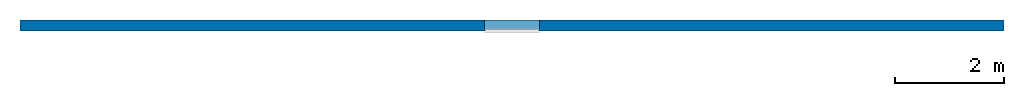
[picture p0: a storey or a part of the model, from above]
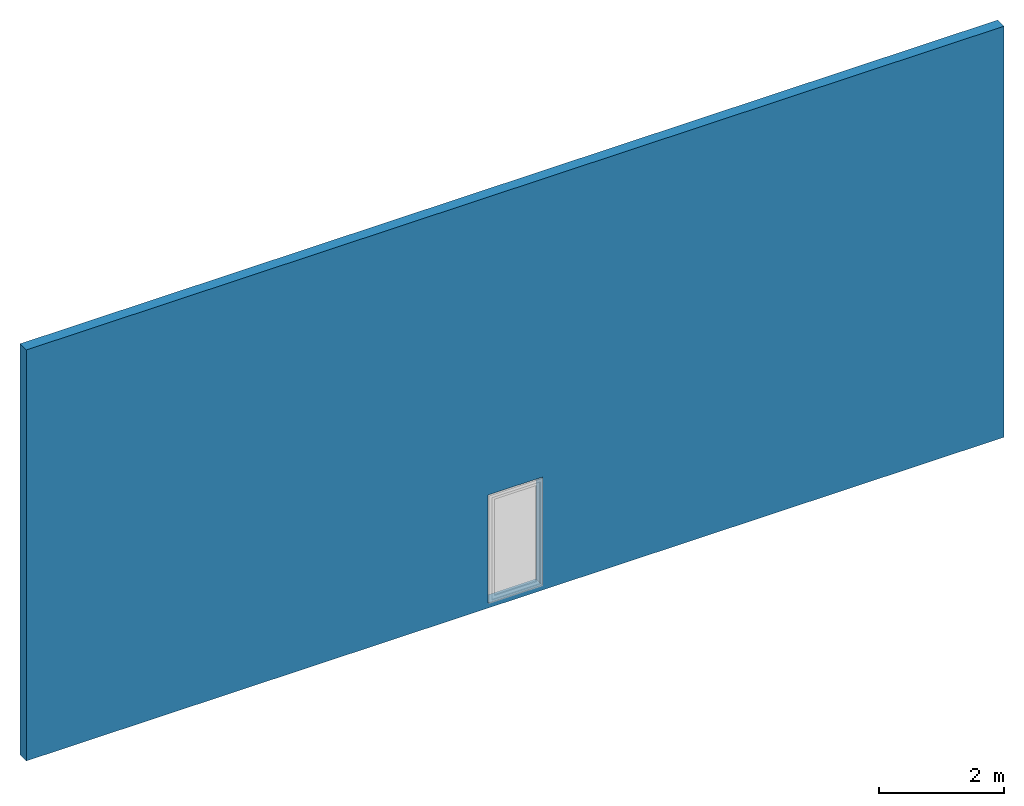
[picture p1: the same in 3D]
Properties of the parts of a building model (IFC2X3)

# File
Description: ViewDefinition [CoordinationView_V2.0]
File name: 0001
Time: 2021-01-22T09:44:21
Written by: The EXPRESS Data Manager Version 5.02.0100.07 : 28 Aug 2013
Made in: 20180328_1600(x64) - Exporter 19.0.1.1 - IU alternativa 19.0.1.1
Comment: STEP Physical File produced by: The EXPRESS Data Manager Version 5.02.0100.07 : 28 Aug 2013 * Module: EDMstepFileFactory/EDMstandAlone * Creation date: Fri Jan 22 09:44:21 2021 * Host: DESKTOP-H3U9LF2 * Database: C:\Users\BIMTOOL3\AppData\Local\Temp\{1FAAF69B-8FC0-4C08-A9C9-90A2DEA5AE0A}\ifc * Database version: 5507 * Database creation date: Fri Jan 22 09:44:20 2021 * Schema: IFC2X3 * Model: DataRepository.ifc * Model creation date: Fri Jan 22 09:44:21 2021 * Header model: DataRepository.ifc_HeaderModel * Header model creation date: Fri Jan 22 09:44:21 2021 * EDMuser: sdai-user * EDMgroup: sdai-group * License ID and type: 5605 : Permanent license. Expiry date: * EDMstepFileFactory options: 020000

# IfcProject, 0001
LongName: Nombre de proyecto; Phase: Estado de proyecto

# IfcSite, Default
RefLatitude: 42, 12, 46, 804504; RefLongitude: -71, -2, 0, -602416; RefElevation: 0 mm

# IfcBuilding
Pset_BuildingCommon - NumberOfStoreys: 1

# IfcBuildingStorey, Nivel 1
LongName: Nivel 1; Elevation: 0 mm

# IfcBuildingElementProxy: 5.1 REH_ED-60 H Z74, 5.1 REH_ED-60 H Z74 :5.1 REH_ED-60 H Z74:347606
In: Nivel 1
Type - Material: Glass, RAU-PVC
Pset_BuildingElementProxyCommon - Reference: 5.1 REH_ED-60 H Z74
Pset_ManufacturerTypeInformation - Manufacturer: REHAU

# IfcWallStandardCase: Muro básico:Genérico - 200 mm, Muro básico:Genérico - 200 mm:347595
In: Nivel 1
Type - PredefinedType: STANDARD; Material: Muro por defecto 200 mm
Pset_WallCommon - Reference: Genérico - 200 mm; LoadBearing: no; ExtendToStructure: no; IsExternal: yes
